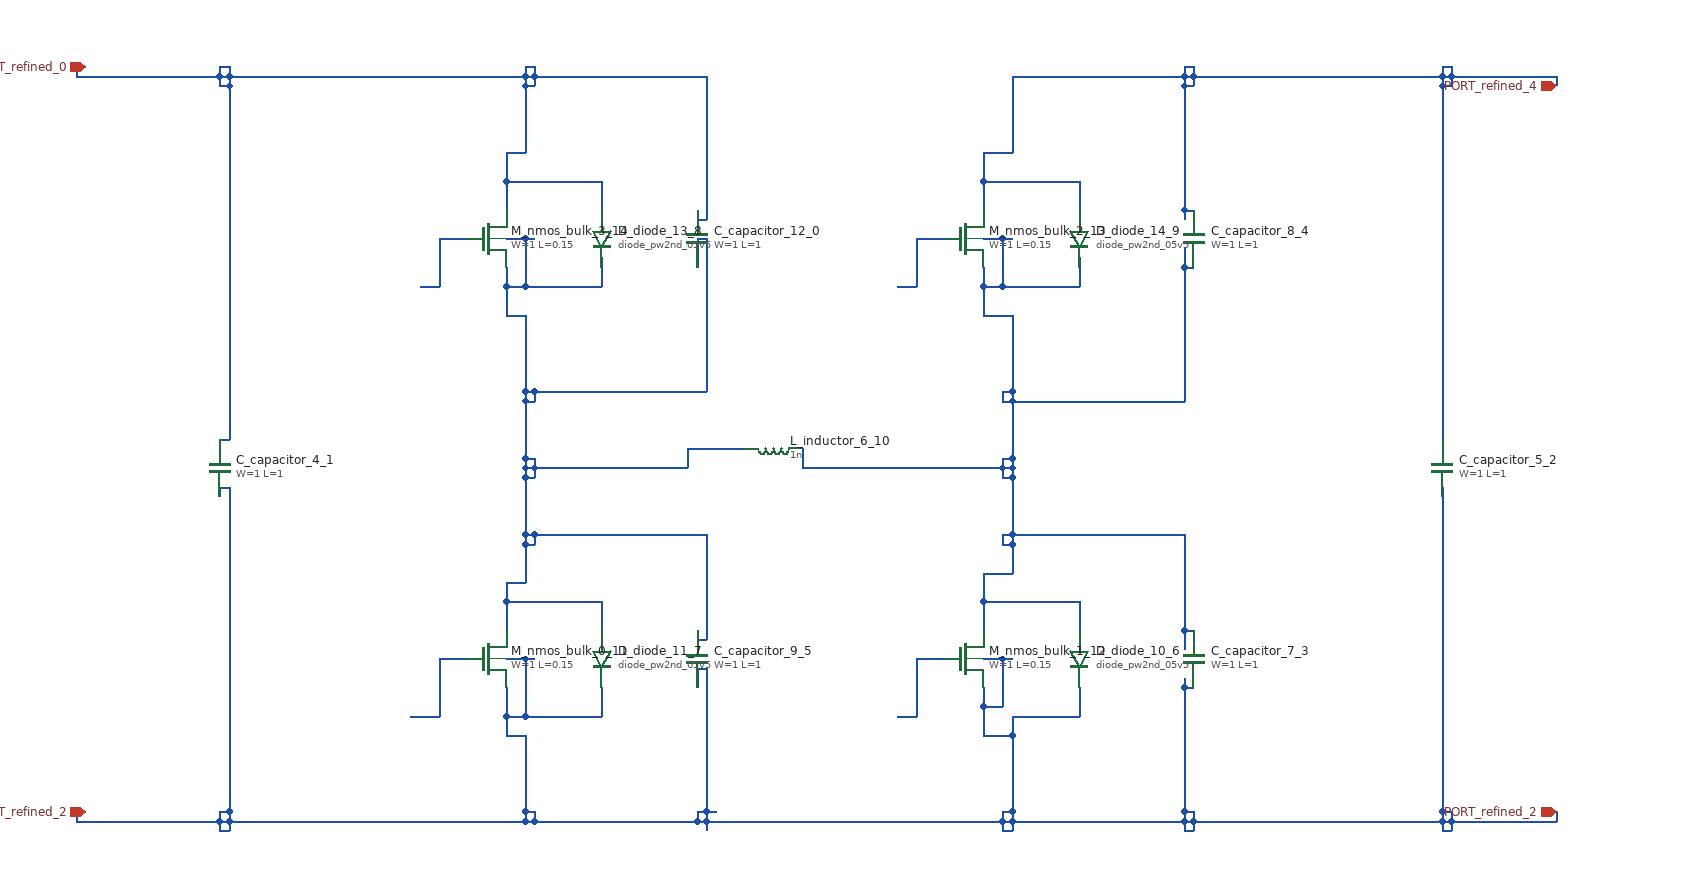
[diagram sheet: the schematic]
v {xschem version=3.4.8 file_version=1.2}
G {}
K {}
V {}
S {}
E {}
C {sky130_fd_pr/cap_mim_m3_1.sym} 760 360 2 0 {name="C_capacitor_12_0" model=cap_mim_m3_1 W=1 L=1 MF=1 spiceprefix=X}
C {sky130_fd_pr/cap_mim_m3_1.sym} 260 600 2 0 {name="C_capacitor_4_1" model=cap_mim_m3_1 W=1 L=1 MF=1 spiceprefix=X}
C {sky130_fd_pr/cap_mim_m3_1.sym} 1540 600 2 0 {name="C_capacitor_5_2" model=cap_mim_m3_1 W=1 L=1 MF=1 spiceprefix=X}
C {sky130_fd_pr/cap_mim_m3_1.sym} 1280 800 2 0 {name="C_capacitor_7_3" model=cap_mim_m3_1 W=1 L=1 MF=1 spiceprefix=X}
C {sky130_fd_pr/cap_mim_m3_1.sym} 1280 360 2 0 {name="C_capacitor_8_4" model=cap_mim_m3_1 W=1 L=1 MF=1 spiceprefix=X}
C {sky130_fd_pr/cap_mim_m3_1.sym} 760 800 2 0 {name="C_capacitor_9_5" model=cap_mim_m3_1 W=1 L=1 MF=1 spiceprefix=X}
C {sky130_fd_pr/diode.sym} 1160 800 0 0 {name="D_diode_10_6"
model=diode_pw2nd_05v5
area=1e12
perim=4e6
spiceprefix=X
}
C {sky130_fd_pr/diode.sym} 660 800 0 0 {name="D_diode_11_7"
model=diode_pw2nd_05v5
area=1e12
perim=4e6
spiceprefix=X
}
C {sky130_fd_pr/diode.sym} 660 360 0 0 {name="D_diode_13_8"
model=diode_pw2nd_05v5
area=1e12
perim=4e6
spiceprefix=X
}
C {sky130_fd_pr/diode.sym} 1160 360 0 0 {name="D_diode_14_9"
model=diode_pw2nd_05v5
area=1e12
perim=4e6
spiceprefix=X
}
C {devices/ind.sym} 840 580 1 0 {name="L_inductor_6_10"
m=1
value=1n
footprint=1206
device=inductor}
C {sky130_fd_pr/nfet_01v8.sym} 540 800 0 0 {name="M_nmos_bulk_0_11"
W=1
L=0.15
nf=1 
mult=1
ad="expr('int((@nf + 1)/2) * @W / @nf * 0.29')"
pd="expr('2*int((@nf + 1)/2) * (@W / @nf + 0.29)')"
as="expr('int((@nf + 2)/2) * @W / @nf * 0.29')"
ps="expr('2*int((@nf + 2)/2) * (@W / @nf + 0.29)')"
nrd="expr('0.29 / @W ')" nrs="expr('0.29 / @W ')"
sa=0 sb=0 sd=0
model=nfet_01v8
spiceprefix=X
}
C {sky130_fd_pr/nfet_01v8.sym} 1040 800 0 0 {name="M_nmos_bulk_1_12"
W=1
L=0.15
nf=1 
mult=1
ad="expr('int((@nf + 1)/2) * @W / @nf * 0.29')"
pd="expr('2*int((@nf + 1)/2) * (@W / @nf + 0.29)')"
as="expr('int((@nf + 2)/2) * @W / @nf * 0.29')"
ps="expr('2*int((@nf + 2)/2) * (@W / @nf + 0.29)')"
nrd="expr('0.29 / @W ')" nrs="expr('0.29 / @W ')"
sa=0 sb=0 sd=0
model=nfet_01v8
spiceprefix=X
}
C {sky130_fd_pr/nfet_01v8.sym} 1040 360 0 0 {name="M_nmos_bulk_2_13"
W=1
L=0.15
nf=1 
mult=1
ad="expr('int((@nf + 1)/2) * @W / @nf * 0.29')"
pd="expr('2*int((@nf + 1)/2) * (@W / @nf + 0.29)')"
as="expr('int((@nf + 2)/2) * @W / @nf * 0.29')"
ps="expr('2*int((@nf + 2)/2) * (@W / @nf + 0.29)')"
nrd="expr('0.29 / @W ')" nrs="expr('0.29 / @W ')"
sa=0 sb=0 sd=0
model=nfet_01v8
spiceprefix=X
}
C {sky130_fd_pr/nfet_01v8.sym} 540 360 0 0 {name="M_nmos_bulk_3_14"
W=1
L=0.15
nf=1 
mult=1
ad="expr('int((@nf + 1)/2) * @W / @nf * 0.29')"
pd="expr('2*int((@nf + 1)/2) * (@W / @nf + 0.29)')"
as="expr('int((@nf + 2)/2) * @W / @nf * 0.29')"
ps="expr('2*int((@nf + 2)/2) * (@W / @nf + 0.29)')"
nrd="expr('0.29 / @W ')" nrs="expr('0.29 / @W ')"
sa=0 sb=0 sd=0
model=nfet_01v8
spiceprefix=X
}
C {devices/ipin.sym} 1660 960 0 0 {name="p_port_16_15" lab="PORT_refined_2"}
C {devices/ipin.sym} 120 960 0 0 {name="p_port_17_16" lab="PORT_refined_2"}
C {devices/ipin.sym} 1660 200 0 0 {name="p_port_18_17" lab="PORT_refined_4"}
C {devices/ipin.sym} 120 180 0 0 {name="p_port_19_18" lab="PORT_refined_0"}
N 260 570 270 570 {}
N 760 340 770 340 {}
N 560 300 660 300 {}
N 560 270 580 270 {}
N 260 200 270 200 {}
N 580 200 590 200 {}
N 110 190 260 190 {}
N 260 190 270 190 {}
N 270 190 580 190 {}
N 580 190 590 190 {}
N 590 190 770 190 {}
N 110 180 120 180 {}
N 260 180 270 180 {}
N 580 180 590 180 {}
N 110 190 110 180 {}
N 260 200 260 190 {}
N 260 190 260 180 {}
N 270 570 270 200 {}
N 270 200 270 190 {}
N 270 190 270 180 {}
N 560 330 560 300 {}
N 560 300 560 270 {}
N 580 270 580 200 {}
N 580 200 580 190 {}
N 580 190 580 180 {}
N 590 200 590 190 {}
N 590 190 590 180 {}
N 660 330 660 300 {}
N 760 340 760 330 {}
N 770 340 770 190 {}
N 760 780 770 780 {}
N 560 740 660 740 {}
N 560 720 580 720 {}
N 580 680 590 680 {}
N 580 670 590 670 {}
N 590 670 770 670 {}
N 580 610 590 610 {}
N 580 600 590 600 {}
N 590 600 750 600 {}
N 580 590 590 590 {}
N 750 580 810 580 {}
N 580 530 590 530 {}
N 580 520 590 520 {}
N 590 520 770 520 {}
N 560 440 580 440 {}
N 560 410 580 410 {}
N 580 410 660 410 {}
N 560 360 580 360 {}
N 580 360 590 360 {}
N 760 360 770 360 {}
N 560 770 560 740 {}
N 560 740 560 720 {}
N 560 440 560 410 {}
N 560 410 560 390 {}
N 580 720 580 680 {}
N 580 680 580 670 {}
N 580 670 580 610 {}
N 580 610 580 600 {}
N 580 600 580 590 {}
N 580 590 580 530 {}
N 580 530 580 520 {}
N 580 520 580 440 {}
N 580 410 580 360 {}
N 590 680 590 670 {}
N 590 610 590 600 {}
N 590 600 590 590 {}
N 590 530 590 520 {}
N 660 770 660 740 {}
N 660 410 660 390 {}
N 660 390 660 380 {}
N 750 600 750 580 {}
N 760 780 760 770 {}
N 760 390 760 360 {}
N 770 780 770 670 {}
N 770 520 770 360 {}
N 260 980 270 980 {}
N 1080 980 1090 980 {}
N 1270 980 1280 980 {}
N 1540 980 1550 980 {}
N 110 970 260 970 {}
N 260 970 270 970 {}
N 270 970 580 970 {}
N 580 970 590 970 {}
N 590 970 760 970 {}
N 760 970 770 970 {}
N 770 970 1080 970 {}
N 1080 970 1090 970 {}
N 1090 970 1270 970 {}
N 1270 970 1280 970 {}
N 1280 970 1540 970 {}
N 1540 970 1550 970 {}
N 1550 970 1660 970 {}
N 110 960 120 960 {}
N 260 960 270 960 {}
N 580 960 590 960 {}
N 760 960 770 960 {}
N 770 960 780 960 {}
N 1080 960 1090 960 {}
N 1270 960 1280 960 {}
N 1540 960 1550 960 {}
N 560 880 580 880 {}
N 1060 880 1090 880 {}
N 560 860 580 860 {}
N 580 860 660 860 {}
N 1090 860 1160 860 {}
N 1060 850 1080 850 {}
N 1270 830 1280 830 {}
N 760 810 770 810 {}
N 560 800 580 800 {}
N 580 800 590 800 {}
N 1060 800 1080 800 {}
N 1080 800 1090 800 {}
N 260 620 270 620 {}
N 110 970 110 960 {}
N 260 980 260 970 {}
N 260 970 260 960 {}
N 260 630 260 620 {}
N 270 980 270 970 {}
N 270 970 270 960 {}
N 270 960 270 620 {}
N 560 880 560 860 {}
N 560 860 560 830 {}
N 580 970 580 960 {}
N 580 960 580 880 {}
N 580 860 580 800 {}
N 590 970 590 960 {}
N 660 860 660 830 {}
N 760 970 760 960 {}
N 760 830 760 810 {}
N 770 980 770 970 {}
N 770 970 770 960 {}
N 770 960 770 810 {}
N 1060 880 1060 850 {}
N 1060 850 1060 830 {}
N 1080 980 1080 970 {}
N 1080 970 1080 960 {}
N 1080 850 1080 800 {}
N 1090 980 1090 970 {}
N 1090 970 1090 960 {}
N 1090 960 1090 880 {}
N 1090 880 1090 860 {}
N 1160 860 1160 830 {}
N 1270 980 1270 970 {}
N 1270 970 1270 960 {}
N 1270 960 1270 830 {}
N 1270 830 1270 820 {}
N 1280 980 1280 970 {}
N 1280 970 1280 960 {}
N 1540 980 1540 970 {}
N 1540 970 1540 960 {}
N 1540 960 1540 630 {}
N 1540 630 1540 620 {}
N 1550 980 1550 970 {}
N 1550 970 1550 960 {}
N 1660 970 1660 960 {}
N 1270 770 1280 770 {}
N 1060 740 1160 740 {}
N 1060 710 1090 710 {}
N 1080 680 1090 680 {}
N 1080 670 1090 670 {}
N 1090 670 1270 670 {}
N 1080 610 1090 610 {}
N 870 600 1080 600 {}
N 1080 600 1090 600 {}
N 1080 590 1090 590 {}
N 1080 530 1090 530 {}
N 1090 530 1270 530 {}
N 1080 520 1090 520 {}
N 1060 440 1090 440 {}
N 1060 410 1080 410 {}
N 1080 410 1160 410 {}
N 1270 390 1280 390 {}
N 1060 360 1080 360 {}
N 1080 360 1090 360 {}
N 870 600 870 580 {}
N 1060 770 1060 740 {}
N 1060 740 1060 710 {}
N 1060 440 1060 410 {}
N 1060 410 1060 390 {}
N 1080 680 1080 670 {}
N 1080 610 1080 600 {}
N 1080 600 1080 590 {}
N 1080 530 1080 520 {}
N 1080 410 1080 360 {}
N 1090 710 1090 680 {}
N 1090 680 1090 670 {}
N 1090 670 1090 610 {}
N 1090 610 1090 600 {}
N 1090 600 1090 590 {}
N 1090 590 1090 530 {}
N 1090 530 1090 520 {}
N 1090 520 1090 440 {}
N 1160 770 1160 740 {}
N 1160 410 1160 390 {}
N 1160 390 1160 380 {}
N 1270 790 1270 770 {}
N 1270 770 1270 670 {}
N 1270 530 1270 390 {}
N 1270 390 1270 370 {}
N 1270 330 1280 330 {}
N 1060 300 1160 300 {}
N 1060 270 1090 270 {}
N 1270 200 1280 200 {}
N 1540 200 1550 200 {}
N 1090 190 1270 190 {}
N 1270 190 1280 190 {}
N 1280 190 1540 190 {}
N 1540 190 1550 190 {}
N 1550 190 1660 190 {}
N 1270 180 1280 180 {}
N 1540 180 1550 180 {}
N 1060 330 1060 300 {}
N 1060 300 1060 270 {}
N 1090 270 1090 190 {}
N 1160 330 1160 300 {}
N 1270 340 1270 330 {}
N 1270 330 1270 200 {}
N 1270 200 1270 190 {}
N 1270 190 1270 180 {}
N 1280 200 1280 190 {}
N 1280 190 1280 180 {}
N 1540 570 1540 200 {}
N 1540 200 1540 190 {}
N 1540 190 1540 180 {}
N 1550 200 1550 190 {}
N 1550 190 1550 180 {}
N 1660 200 1660 190 {}
N 460 860 490 860 {}
N 490 800 520 800 {}
N 490 860 490 800 {}
N 970 860 990 860 {}
N 990 800 1020 800 {}
N 990 860 990 800 {}
N 970 410 990 410 {}
N 990 360 1020 360 {}
N 990 410 990 360 {}
N 470 410 490 410 {}
N 490 360 520 360 {}
N 490 410 490 360 {}
